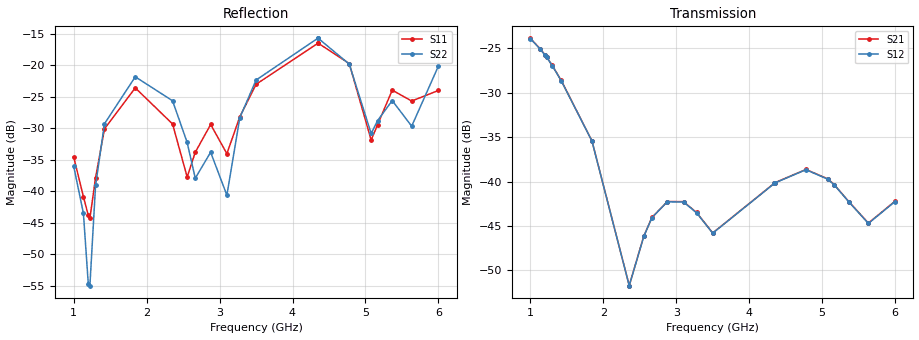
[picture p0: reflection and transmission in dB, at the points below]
!Agilent Technologies,E8364B,MY43040528,A.07.50.67
!Agilent E8364B: A.07.50.67
!Date: Sunday, March 01, 2026 22:22:04
!Correction: S11(Full 2 Port(1,2))
!S21(Full 2 Port(1,2))
!S12(Full 2 Port(1,2))
!S22(Full 2 Port(1,2))
!S2P File: Measurements: S11, S21, S12, S22:
# Hz S  dB  R 50
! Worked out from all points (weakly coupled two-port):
!   451 points, 1 GHz to 6 GHz, reference 50 ohm
!   highest |S21| = -23.88 dB at 1 GHz (marker M1); lowest = -51.7 dB at 2.356 GHz (marker M2)
!   lowest |S11| = -44.3 dB at 1.222 GHz (marker M3), VSWR 1.01, Z = 50.3 - j0.545 ohm
!   |S11| at or under -10 dB: start of sweep to end of sweep
!   |S22| runs from -57.0 to -15.7 dB; largest |S21 - S12| = 0.00025
!   S11 on the Smith chart (normalised r, x): 1 GHz: 1.04, +0.01; 4.356 GHz: 1.20, -0.26; 6 GHz: 0.96, -0.12
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1e9  -34.55 12.3  -23.88 154.9  -23.91 155.0  -36.03 -31.0
1.133333e9  -40.86 -9.7  -25.04 78.9  -25.07 78.9  -43.51 -23.7
1.2e9  -43.84 -40.3  -25.73 41.0  -25.76 41.0  -54.68 24.9
1.222222e9  -44.32 -62.9  -25.97 28.4  -26.00 28.5  -55.02 102.1
1.3e9  -37.85 -130.6  -26.91 -15.4  -26.95 -15.3  -39.09 128.1
1.422222e9  -30.09 -177.2  -28.60 -83.0  -28.64 -83.0  -29.28 98.4
1.844444e9  -23.58 83.0  -35.42 51.5  -35.44 51.6  -21.82 -11.2
2.355556e9  -29.32 13.1  -51.71 -148.8  -51.73 -148.8  -25.63 -115.7
2.555556e9  -37.74 32.1  -46.13 157.3  -46.18 157.2  -32.26 -148.2
2.666667e9  -33.82 67.1  -44.05 103.9  -44.07 103.9  -37.94 -127.8
2.877778e9  -29.40 44.9  -42.25 -4.7  -42.28 -4.7  -33.81 -115.6
3.1e9  -34.04 45.3  -42.27 -121.1  -42.31 -121.1  -40.64 -94.4
3.277778e9  -28.16 76.8  -43.48 148.5  -43.52 148.6  -28.31 -75.1
3.5e9  -23.01 49.4  -45.79 46.8  -45.82 46.9  -22.34 -121.7
4.344444e9  -16.52 -44.2  -40.19 23.7  -40.22 23.8  -15.71 100.2
4.355556e9  -16.51 -45.9  -40.12 17.8  -40.15 17.8  -15.73 98.0
4.777778e9  -19.71 -115.7  -38.64 142.5  -38.67 142.6  -19.81 13.6
5.077778e9  -31.87 -113.1  -39.70 -33.7  -39.74 -33.7  -30.83 11.2
5.166667e9  -29.42 -77.7  -40.35 -87.4  -40.39 -87.4  -28.77 29.5
5.366667e9  -23.94 -91.7  -42.27 147.3  -42.30 147.3  -25.60 7.6
5.633333e9  -25.67 -117.3  -44.68 -38.4  -44.72 -38.4  -29.67 4.7
6e9  -23.99 -104.7  -42.21 59.8  -42.25 59.8  -20.11 -19.3
